VERSION 5.7 ;
  NOWIREEXTENSIONATPIN ON ;
  DIVIDERCHAR "/" ;
  BUSBITCHARS "[]" ;
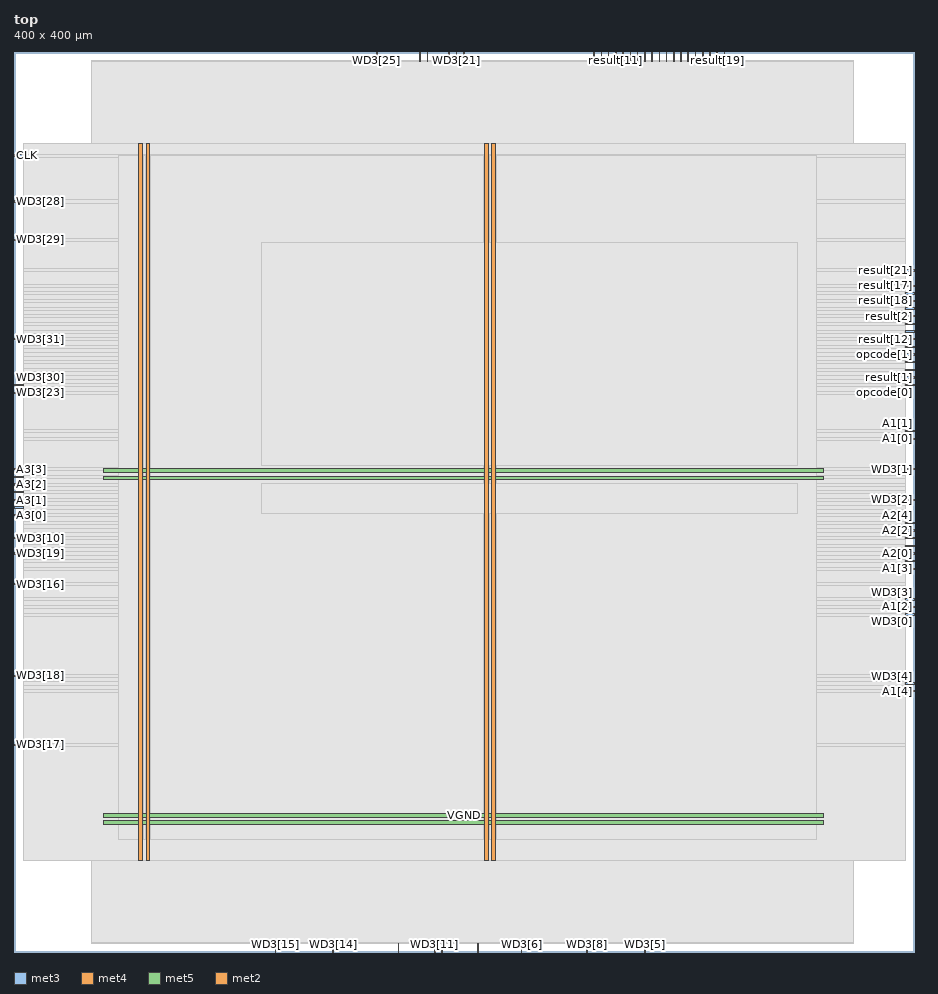
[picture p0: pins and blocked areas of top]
MACRO top
  CLASS BLOCK ;
  FOREIGN top ;
  ORIGIN 0.000 0.000 ;
  SIZE 400.000 BY 400.000 ;
  PIN A1[0]
    DIRECTION INPUT ;
    USE SIGNAL ;
    ANTENNAGATEAREA 0.126000 ;
    PORT
      LAYER met3 ;
        RECT 396.000 227.840 400.000 228.440 ;
    END
  END A1[0]
  PIN A1[1]
    DIRECTION INPUT ;
    USE SIGNAL ;
    ANTENNAGATEAREA 0.196500 ;
    PORT
      LAYER met3 ;
        RECT 396.000 231.240 400.000 231.840 ;
    END
  END A1[1]
  PIN A1[2]
    DIRECTION INPUT ;
    USE SIGNAL ;
    ANTENNAGATEAREA 0.247500 ;
    PORT
      LAYER met3 ;
        RECT 396.000 153.040 400.000 153.640 ;
    END
  END A1[2]
  PIN A1[3]
    DIRECTION INPUT ;
    USE SIGNAL ;
    ANTENNAGATEAREA 0.196500 ;
    PORT
      LAYER met3 ;
        RECT 396.000 170.040 400.000 170.640 ;
    END
  END A1[3]
  PIN A1[4]
    DIRECTION INPUT ;
    USE SIGNAL ;
    ANTENNAGATEAREA 0.213000 ;
    PORT
      LAYER met3 ;
        RECT 396.000 115.640 400.000 116.240 ;
    END
  END A1[4]
  PIN A2[0]
    DIRECTION INPUT ;
    USE SIGNAL ;
    ANTENNAGATEAREA 2.832000 ;
    PORT
      LAYER met3 ;
        RECT 396.000 173.440 400.000 174.040 ;
    END
  END A2[0]
  PIN A2[1]
    DIRECTION INPUT ;
    USE SIGNAL ;
    ANTENNAGATEAREA 0.886500 ;
    PORT
      LAYER met3 ;
        RECT 396.000 176.840 400.000 177.440 ;
    END
  END A2[1]
  PIN A2[2]
    DIRECTION INPUT ;
    USE SIGNAL ;
    ANTENNAGATEAREA 0.213000 ;
    ANTENNADIFFAREA 0.434700 ;
    PORT
      LAYER met3 ;
        RECT 396.000 187.040 400.000 187.640 ;
    END
  END A2[2]
  PIN A2[3]
    DIRECTION INPUT ;
    USE SIGNAL ;
    ANTENNAGATEAREA 0.213000 ;
    ANTENNADIFFAREA 0.434700 ;
    PORT
      LAYER met3 ;
        RECT 396.000 180.240 400.000 180.840 ;
    END
  END A2[3]
  PIN A2[4]
    DIRECTION INPUT ;
    USE SIGNAL ;
    ANTENNAGATEAREA 0.213000 ;
    PORT
      LAYER met3 ;
        RECT 396.000 190.440 400.000 191.040 ;
    END
  END A2[4]
  PIN A3[0]
    DIRECTION INPUT ;
    USE SIGNAL ;
    ANTENNAGATEAREA 0.159000 ;
    ANTENNADIFFAREA 0.434700 ;
    PORT
      LAYER met3 ;
        RECT 0.000 193.840 4.000 194.440 ;
    END
  END A3[0]
  PIN A3[1]
    DIRECTION INPUT ;
    USE SIGNAL ;
    ANTENNAGATEAREA 0.159000 ;
    ANTENNADIFFAREA 0.434700 ;
    PORT
      LAYER met3 ;
        RECT 0.000 197.240 4.000 197.840 ;
    END
  END A3[1]
  PIN A3[2]
    DIRECTION INPUT ;
    USE SIGNAL ;
    ANTENNAGATEAREA 0.196500 ;
    ANTENNADIFFAREA 0.434700 ;
    PORT
      LAYER met3 ;
        RECT 0.000 204.040 4.000 204.640 ;
    END
  END A3[2]
  PIN A3[3]
    DIRECTION INPUT ;
    USE SIGNAL ;
    ANTENNAGATEAREA 0.196500 ;
    PORT
      LAYER met3 ;
        RECT 0.000 210.840 4.000 211.440 ;
    END
  END A3[3]
  PIN A3[4]
    DIRECTION INPUT ;
    USE SIGNAL ;
    ANTENNAGATEAREA 0.196500 ;
    PORT
      LAYER met3 ;
        RECT 0.000 207.440 4.000 208.040 ;
    END
  END A3[4]
  PIN CLK
    DIRECTION INPUT ;
    USE SIGNAL ;
    ANTENNAGATEAREA 0.852000 ;
    PORT
      LAYER met3 ;
        RECT 0.000 353.640 4.000 354.240 ;
    END
  END CLK
  PIN VGND
    DIRECTION INOUT ;
    USE GROUND ;
    PORT
      LAYER met4 ;
        RECT 58.840 40.560 60.440 359.280 ;
    END
    PORT
      LAYER met4 ;
        RECT 212.440 40.560 214.040 359.280 ;
    END
    PORT
      LAYER met5 ;
        RECT 39.780 59.950 359.960 61.550 ;
    END
    PORT
      LAYER met5 ;
        RECT 39.780 213.130 359.960 214.730 ;
    END
  END VGND
  PIN VPWR
    DIRECTION INOUT ;
    USE POWER ;
    PORT
      LAYER met4 ;
        RECT 55.540 40.560 57.140 359.280 ;
    END
    PORT
      LAYER met4 ;
        RECT 209.140 40.560 210.740 359.280 ;
    END
    PORT
      LAYER met5 ;
        RECT 39.780 56.650 359.960 58.250 ;
    END
    PORT
      LAYER met5 ;
        RECT 39.780 209.830 359.960 211.430 ;
    END
  END VPWR
  PIN WD3[0]
    DIRECTION INPUT ;
    USE SIGNAL ;
    ANTENNAGATEAREA 0.196500 ;
    PORT
      LAYER met3 ;
        RECT 396.000 149.640 400.000 150.240 ;
    END
  END WD3[0]
  PIN WD3[10]
    DIRECTION INPUT ;
    USE SIGNAL ;
    ANTENNAGATEAREA 0.126000 ;
    ANTENNADIFFAREA 0.434700 ;
    PORT
      LAYER met3 ;
        RECT 0.000 183.640 4.000 184.240 ;
    END
  END WD3[10]
  PIN WD3[11]
    DIRECTION INPUT ;
    USE SIGNAL ;
    ANTENNAGATEAREA 0.213000 ;
    PORT
      LAYER met2 ;
        RECT 186.850 0.000 187.130 4.000 ;
    END
  END WD3[11]
  PIN WD3[12]
    DIRECTION INPUT ;
    USE SIGNAL ;
    ANTENNAGATEAREA 0.196500 ;
    PORT
      LAYER met2 ;
        RECT 170.750 0.000 171.030 4.000 ;
    END
  END WD3[12]
  PIN WD3[13]
    DIRECTION INPUT ;
    USE SIGNAL ;
    ANTENNAGATEAREA 0.126000 ;
    PORT
      LAYER met2 ;
        RECT 190.070 0.000 190.350 4.000 ;
    END
  END WD3[13]
  PIN WD3[14]
    DIRECTION INPUT ;
    USE SIGNAL ;
    ANTENNAGATEAREA 0.196500 ;
    PORT
      LAYER met2 ;
        RECT 141.770 0.000 142.050 4.000 ;
    END
  END WD3[14]
  PIN WD3[15]
    DIRECTION INPUT ;
    USE SIGNAL ;
    ANTENNAGATEAREA 0.196500 ;
    PORT
      LAYER met2 ;
        RECT 116.010 0.000 116.290 4.000 ;
    END
  END WD3[15]
  PIN WD3[16]
    DIRECTION INPUT ;
    USE SIGNAL ;
    ANTENNAGATEAREA 0.196500 ;
    PORT
      LAYER met3 ;
        RECT 0.000 163.240 4.000 163.840 ;
    END
  END WD3[16]
  PIN WD3[17]
    DIRECTION INPUT ;
    USE SIGNAL ;
    ANTENNAGATEAREA 0.196500 ;
    PORT
      LAYER met3 ;
        RECT 0.000 91.840 4.000 92.440 ;
    END
  END WD3[17]
  PIN WD3[18]
    DIRECTION INPUT ;
    USE SIGNAL ;
    ANTENNAGATEAREA 0.196500 ;
    PORT
      LAYER met3 ;
        RECT 0.000 122.440 4.000 123.040 ;
    END
  END WD3[18]
  PIN WD3[19]
    DIRECTION INPUT ;
    USE SIGNAL ;
    ANTENNAGATEAREA 0.196500 ;
    PORT
      LAYER met3 ;
        RECT 0.000 176.840 4.000 177.440 ;
    END
  END WD3[19]
  PIN WD3[1]
    DIRECTION INPUT ;
    USE SIGNAL ;
    ANTENNAGATEAREA 0.196500 ;
    PORT
      LAYER met3 ;
        RECT 396.000 214.240 400.000 214.840 ;
    END
  END WD3[1]
  PIN WD3[20]
    DIRECTION INPUT ;
    USE SIGNAL ;
    ANTENNAGATEAREA 0.126000 ;
    ANTENNADIFFAREA 0.434700 ;
    PORT
      LAYER met3 ;
        RECT 0.000 214.240 4.000 214.840 ;
    END
  END WD3[20]
  PIN WD3[21]
    DIRECTION INPUT ;
    USE SIGNAL ;
    ANTENNAGATEAREA 0.126000 ;
    PORT
      LAYER met2 ;
        RECT 196.510 396.000 196.790 400.000 ;
    END
  END WD3[21]
  PIN WD3[22]
    DIRECTION INPUT ;
    USE SIGNAL ;
    ANTENNAGATEAREA 0.213000 ;
    PORT
      LAYER met2 ;
        RECT 193.290 396.000 193.570 400.000 ;
    END
  END WD3[22]
  PIN WD3[23]
    DIRECTION INPUT ;
    USE SIGNAL ;
    ANTENNAGATEAREA 0.126000 ;
    ANTENNADIFFAREA 0.434700 ;
    PORT
      LAYER met3 ;
        RECT 0.000 248.240 4.000 248.840 ;
    END
  END WD3[23]
  PIN WD3[24]
    DIRECTION INPUT ;
    USE SIGNAL ;
    ANTENNAGATEAREA 0.196500 ;
    PORT
      LAYER met2 ;
        RECT 199.730 396.000 200.010 400.000 ;
    END
  END WD3[24]
  PIN WD3[25]
    DIRECTION INPUT ;
    USE SIGNAL ;
    ANTENNAGATEAREA 0.196500 ;
    PORT
      LAYER met2 ;
        RECT 161.090 396.000 161.370 400.000 ;
    END
  END WD3[25]
  PIN WD3[26]
    DIRECTION INPUT ;
    USE SIGNAL ;
    ANTENNAGATEAREA 0.196500 ;
    PORT
      LAYER met2 ;
        RECT 180.410 396.000 180.690 400.000 ;
    END
  END WD3[26]
  PIN WD3[27]
    DIRECTION INPUT ;
    USE SIGNAL ;
    ANTENNAGATEAREA 0.196500 ;
    PORT
      LAYER met2 ;
        RECT 183.630 396.000 183.910 400.000 ;
    END
  END WD3[27]
  PIN WD3[28]
    DIRECTION INPUT ;
    USE SIGNAL ;
    ANTENNAGATEAREA 0.196500 ;
    PORT
      LAYER met3 ;
        RECT 0.000 333.240 4.000 333.840 ;
    END
  END WD3[28]
  PIN WD3[29]
    DIRECTION INPUT ;
    USE SIGNAL ;
    ANTENNAGATEAREA 0.196500 ;
    PORT
      LAYER met3 ;
        RECT 0.000 316.240 4.000 316.840 ;
    END
  END WD3[29]
  PIN WD3[2]
    DIRECTION INPUT ;
    USE SIGNAL ;
    ANTENNAGATEAREA 0.196500 ;
    PORT
      LAYER met3 ;
        RECT 396.000 200.640 400.000 201.240 ;
    END
  END WD3[2]
  PIN WD3[30]
    DIRECTION INPUT ;
    USE SIGNAL ;
    ANTENNAGATEAREA 0.196500 ;
    PORT
      LAYER met3 ;
        RECT 0.000 251.640 4.000 252.240 ;
    END
  END WD3[30]
  PIN WD3[31]
    DIRECTION INPUT ;
    USE SIGNAL ;
    ANTENNAGATEAREA 0.196500 ;
    PORT
      LAYER met3 ;
        RECT 0.000 272.040 4.000 272.640 ;
    END
  END WD3[31]
  PIN WD3[3]
    DIRECTION INPUT ;
    USE SIGNAL ;
    ANTENNAGATEAREA 0.196500 ;
    PORT
      LAYER met3 ;
        RECT 396.000 156.440 400.000 157.040 ;
    END
  END WD3[3]
  PIN WD3[4]
    DIRECTION INPUT ;
    USE SIGNAL ;
    ANTENNAGATEAREA 0.196500 ;
    PORT
      LAYER met3 ;
        RECT 396.000 119.040 400.000 119.640 ;
    END
  END WD3[4]
  PIN WD3[5]
    DIRECTION INPUT ;
    USE SIGNAL ;
    ANTENNAGATEAREA 0.196500 ;
    PORT
      LAYER met2 ;
        RECT 280.230 0.000 280.510 4.000 ;
    END
  END WD3[5]
  PIN WD3[6]
    DIRECTION INPUT ;
    USE SIGNAL ;
    ANTENNAGATEAREA 0.196500 ;
    PORT
      LAYER met2 ;
        RECT 225.490 0.000 225.770 4.000 ;
    END
  END WD3[6]
  PIN WD3[7]
    DIRECTION INPUT ;
    USE SIGNAL ;
    ANTENNAGATEAREA 0.196500 ;
    PORT
      LAYER met2 ;
        RECT 206.170 0.000 206.450 4.000 ;
    END
  END WD3[7]
  PIN WD3[8]
    DIRECTION INPUT ;
    USE SIGNAL ;
    ANTENNAGATEAREA 0.196500 ;
    PORT
      LAYER met2 ;
        RECT 254.470 0.000 254.750 4.000 ;
    END
  END WD3[8]
  PIN WD3[9]
    DIRECTION INPUT ;
    USE SIGNAL ;
    ANTENNAGATEAREA 0.213000 ;
    PORT
      LAYER met3 ;
        RECT 396.000 183.640 400.000 184.240 ;
    END
  END WD3[9]
  PIN WE3
    DIRECTION INPUT ;
    USE SIGNAL ;
    ANTENNAGATEAREA 0.196500 ;
    PORT
      LAYER met3 ;
        RECT 0.000 200.640 4.000 201.240 ;
    END
  END WE3
  PIN opcode[0]
    DIRECTION INPUT ;
    USE SIGNAL ;
    ANTENNAGATEAREA 0.213000 ;
    PORT
      LAYER met3 ;
        RECT 396.000 251.640 400.000 252.240 ;
    END
  END opcode[0]
  PIN opcode[1]
    DIRECTION INPUT ;
    USE SIGNAL ;
    ANTENNAGATEAREA 0.196500 ;
    PORT
      LAYER met3 ;
        RECT 396.000 265.240 400.000 265.840 ;
    END
  END opcode[1]
  PIN result[0]
    DIRECTION OUTPUT ;
    USE SIGNAL ;
    ANTENNADIFFAREA 0.795200 ;
    PORT
      LAYER met3 ;
        RECT 396.000 278.840 400.000 279.440 ;
    END
  END result[0]
  PIN result[10]
    DIRECTION OUTPUT ;
    USE SIGNAL ;
    ANTENNADIFFAREA 0.795200 ;
    PORT
      LAYER met2 ;
        RECT 257.690 396.000 257.970 400.000 ;
    END
  END result[10]
  PIN result[11]
    DIRECTION OUTPUT ;
    USE SIGNAL ;
    ANTENNADIFFAREA 0.795200 ;
    PORT
      LAYER met2 ;
        RECT 267.350 396.000 267.630 400.000 ;
    END
  END result[11]
  PIN result[12]
    DIRECTION OUTPUT ;
    USE SIGNAL ;
    ANTENNADIFFAREA 0.795200 ;
    PORT
      LAYER met3 ;
        RECT 396.000 272.040 400.000 272.640 ;
    END
  END result[12]
  PIN result[13]
    DIRECTION OUTPUT ;
    USE SIGNAL ;
    ANTENNADIFFAREA 0.795200 ;
    PORT
      LAYER met3 ;
        RECT 396.000 268.640 400.000 269.240 ;
    END
  END result[13]
  PIN result[14]
    DIRECTION OUTPUT ;
    USE SIGNAL ;
    ANTENNADIFFAREA 0.795200 ;
    PORT
      LAYER met2 ;
        RECT 270.570 396.000 270.850 400.000 ;
    END
  END result[14]
  PIN result[15]
    DIRECTION OUTPUT ;
    USE SIGNAL ;
    ANTENNADIFFAREA 0.795200 ;
    PORT
      LAYER met3 ;
        RECT 396.000 275.440 400.000 276.040 ;
    END
  END result[15]
  PIN result[16]
    DIRECTION OUTPUT ;
    USE SIGNAL ;
    ANTENNADIFFAREA 0.795200 ;
    PORT
      LAYER met2 ;
        RECT 315.650 396.000 315.930 400.000 ;
    END
  END result[16]
  PIN result[17]
    DIRECTION OUTPUT ;
    USE SIGNAL ;
    ANTENNADIFFAREA 0.795200 ;
    PORT
      LAYER met3 ;
        RECT 396.000 295.840 400.000 296.440 ;
    END
  END result[17]
  PIN result[18]
    DIRECTION OUTPUT ;
    USE SIGNAL ;
    ANTENNADIFFAREA 0.795200 ;
    PORT
      LAYER met3 ;
        RECT 396.000 289.040 400.000 289.640 ;
    END
  END result[18]
  PIN result[19]
    DIRECTION OUTPUT ;
    USE SIGNAL ;
    ANTENNADIFFAREA 0.795200 ;
    PORT
      LAYER met2 ;
        RECT 312.430 396.000 312.710 400.000 ;
    END
  END result[19]
  PIN result[1]
    DIRECTION OUTPUT ;
    USE SIGNAL ;
    ANTENNADIFFAREA 0.795200 ;
    PORT
      LAYER met3 ;
        RECT 396.000 255.040 400.000 255.640 ;
    END
  END result[1]
  PIN result[20]
    DIRECTION OUTPUT ;
    USE SIGNAL ;
    ANTENNADIFFAREA 0.795200 ;
    PORT
      LAYER met2 ;
        RECT 289.890 396.000 290.170 400.000 ;
    END
  END result[20]
  PIN result[21]
    DIRECTION OUTPUT ;
    USE SIGNAL ;
    ANTENNADIFFAREA 0.795200 ;
    PORT
      LAYER met3 ;
        RECT 396.000 302.640 400.000 303.240 ;
    END
  END result[21]
  PIN result[22]
    DIRECTION OUTPUT ;
    USE SIGNAL ;
    ANTENNADIFFAREA 0.795200 ;
    PORT
      LAYER met2 ;
        RECT 280.230 396.000 280.510 400.000 ;
    END
  END result[22]
  PIN result[23]
    DIRECTION OUTPUT ;
    USE SIGNAL ;
    ANTENNADIFFAREA 0.795200 ;
    PORT
      LAYER met2 ;
        RECT 273.790 396.000 274.070 400.000 ;
    END
  END result[23]
  PIN result[24]
    DIRECTION OUTPUT ;
    USE SIGNAL ;
    ANTENNADIFFAREA 0.795200 ;
    PORT
      LAYER met2 ;
        RECT 309.210 396.000 309.490 400.000 ;
    END
  END result[24]
  PIN result[25]
    DIRECTION OUTPUT ;
    USE SIGNAL ;
    ANTENNADIFFAREA 0.795200 ;
    PORT
      LAYER met2 ;
        RECT 299.550 396.000 299.830 400.000 ;
    END
  END result[25]
  PIN result[26]
    DIRECTION OUTPUT ;
    USE SIGNAL ;
    ANTENNADIFFAREA 0.795200 ;
    PORT
      LAYER met2 ;
        RECT 305.990 396.000 306.270 400.000 ;
    END
  END result[26]
  PIN result[27]
    DIRECTION OUTPUT ;
    USE SIGNAL ;
    ANTENNADIFFAREA 0.795200 ;
    PORT
      LAYER met2 ;
        RECT 296.330 396.000 296.610 400.000 ;
    END
  END result[27]
  PIN result[28]
    DIRECTION OUTPUT ;
    USE SIGNAL ;
    ANTENNADIFFAREA 0.795200 ;
    PORT
      LAYER met2 ;
        RECT 286.670 396.000 286.950 400.000 ;
    END
  END result[28]
  PIN result[29]
    DIRECTION OUTPUT ;
    USE SIGNAL ;
    ANTENNADIFFAREA 0.795200 ;
    PORT
      LAYER met2 ;
        RECT 283.450 396.000 283.730 400.000 ;
    END
  END result[29]
  PIN result[2]
    DIRECTION OUTPUT ;
    USE SIGNAL ;
    ANTENNADIFFAREA 0.795200 ;
    PORT
      LAYER met3 ;
        RECT 396.000 282.240 400.000 282.840 ;
    END
  END result[2]
  PIN result[30]
    DIRECTION OUTPUT ;
    USE SIGNAL ;
    ANTENNADIFFAREA 0.795200 ;
    PORT
      LAYER met2 ;
        RECT 293.110 396.000 293.390 400.000 ;
    END
  END result[30]
  PIN result[31]
    DIRECTION OUTPUT ;
    USE SIGNAL ;
    ANTENNADIFFAREA 0.891000 ;
    PORT
      LAYER met2 ;
        RECT 260.910 396.000 261.190 400.000 ;
    END
  END result[31]
  PIN result[3]
    DIRECTION OUTPUT ;
    USE SIGNAL ;
    ANTENNADIFFAREA 0.795200 ;
    PORT
      LAYER met3 ;
        RECT 396.000 261.840 400.000 262.440 ;
    END
  END result[3]
  PIN result[4]
    DIRECTION OUTPUT ;
    USE SIGNAL ;
    ANTENNADIFFAREA 0.795200 ;
    PORT
      LAYER met3 ;
        RECT 396.000 285.640 400.000 286.240 ;
    END
  END result[4]
  PIN result[5]
    DIRECTION OUTPUT ;
    USE SIGNAL ;
    ANTENNADIFFAREA 0.795200 ;
    PORT
      LAYER met3 ;
        RECT 396.000 292.440 400.000 293.040 ;
    END
  END result[5]
  PIN result[6]
    DIRECTION OUTPUT ;
    USE SIGNAL ;
    ANTENNADIFFAREA 0.795200 ;
    PORT
      LAYER met2 ;
        RECT 302.770 396.000 303.050 400.000 ;
    END
  END result[6]
  PIN result[7]
    DIRECTION OUTPUT ;
    USE SIGNAL ;
    ANTENNADIFFAREA 0.795200 ;
    PORT
      LAYER met3 ;
        RECT 396.000 258.440 400.000 259.040 ;
    END
  END result[7]
  PIN result[8]
    DIRECTION OUTPUT ;
    USE SIGNAL ;
    ANTENNADIFFAREA 0.795200 ;
    PORT
      LAYER met2 ;
        RECT 277.010 396.000 277.290 400.000 ;
    END
  END result[8]
  PIN result[9]
    DIRECTION OUTPUT ;
    USE SIGNAL ;
    ANTENNADIFFAREA 0.795200 ;
    PORT
      LAYER met2 ;
        RECT 264.130 396.000 264.410 400.000 ;
    END
  END result[9]
  OBS
      LAYER nwell ;
        RECT 39.830 40.715 359.910 359.230 ;
      LAYER li1 ;
        RECT 40.020 40.715 359.720 359.125 ;
      LAYER met1 ;
        RECT 34.570 40.560 372.990 384.500 ;
      LAYER met2 ;
        RECT 34.590 395.720 160.810 396.170 ;
        RECT 161.650 395.720 180.130 396.170 ;
        RECT 180.970 395.720 183.350 396.170 ;
        RECT 184.190 395.720 193.010 396.170 ;
        RECT 193.850 395.720 196.230 396.170 ;
        RECT 197.070 395.720 199.450 396.170 ;
        RECT 200.290 395.720 257.410 396.170 ;
        RECT 258.250 395.720 260.630 396.170 ;
        RECT 261.470 395.720 263.850 396.170 ;
        RECT 264.690 395.720 267.070 396.170 ;
        RECT 267.910 395.720 270.290 396.170 ;
        RECT 271.130 395.720 273.510 396.170 ;
        RECT 274.350 395.720 276.730 396.170 ;
        RECT 277.570 395.720 279.950 396.170 ;
        RECT 280.790 395.720 283.170 396.170 ;
        RECT 284.010 395.720 286.390 396.170 ;
        RECT 287.230 395.720 289.610 396.170 ;
        RECT 290.450 395.720 292.830 396.170 ;
        RECT 293.670 395.720 296.050 396.170 ;
        RECT 296.890 395.720 299.270 396.170 ;
        RECT 300.110 395.720 302.490 396.170 ;
        RECT 303.330 395.720 305.710 396.170 ;
        RECT 306.550 395.720 308.930 396.170 ;
        RECT 309.770 395.720 312.150 396.170 ;
        RECT 312.990 395.720 315.370 396.170 ;
        RECT 316.210 395.720 372.970 396.170 ;
        RECT 34.590 4.280 372.970 395.720 ;
        RECT 34.590 3.670 115.730 4.280 ;
        RECT 116.570 3.670 141.490 4.280 ;
        RECT 142.330 3.670 170.470 4.280 ;
        RECT 171.310 3.670 186.570 4.280 ;
        RECT 187.410 3.670 189.790 4.280 ;
        RECT 190.630 3.670 205.890 4.280 ;
        RECT 206.730 3.670 225.210 4.280 ;
        RECT 226.050 3.670 254.190 4.280 ;
        RECT 255.030 3.670 279.950 4.280 ;
        RECT 280.790 3.670 372.970 4.280 ;
      LAYER met3 ;
        RECT 4.000 354.640 396.000 359.205 ;
        RECT 4.400 353.240 396.000 354.640 ;
        RECT 4.000 334.240 396.000 353.240 ;
        RECT 4.400 332.840 396.000 334.240 ;
        RECT 4.000 317.240 396.000 332.840 ;
        RECT 4.400 315.840 396.000 317.240 ;
        RECT 4.000 303.640 396.000 315.840 ;
        RECT 4.000 302.240 395.600 303.640 ;
        RECT 4.000 296.840 396.000 302.240 ;
        RECT 4.000 295.440 395.600 296.840 ;
        RECT 4.000 293.440 396.000 295.440 ;
        RECT 4.000 292.040 395.600 293.440 ;
        RECT 4.000 290.040 396.000 292.040 ;
        RECT 4.000 288.640 395.600 290.040 ;
        RECT 4.000 286.640 396.000 288.640 ;
        RECT 4.000 285.240 395.600 286.640 ;
        RECT 4.000 283.240 396.000 285.240 ;
        RECT 4.000 281.840 395.600 283.240 ;
        RECT 4.000 279.840 396.000 281.840 ;
        RECT 4.000 278.440 395.600 279.840 ;
        RECT 4.000 276.440 396.000 278.440 ;
        RECT 4.000 275.040 395.600 276.440 ;
        RECT 4.000 273.040 396.000 275.040 ;
        RECT 4.400 271.640 395.600 273.040 ;
        RECT 4.000 269.640 396.000 271.640 ;
        RECT 4.000 268.240 395.600 269.640 ;
        RECT 4.000 266.240 396.000 268.240 ;
        RECT 4.000 264.840 395.600 266.240 ;
        RECT 4.000 262.840 396.000 264.840 ;
        RECT 4.000 261.440 395.600 262.840 ;
        RECT 4.000 259.440 396.000 261.440 ;
        RECT 4.000 258.040 395.600 259.440 ;
        RECT 4.000 256.040 396.000 258.040 ;
        RECT 4.000 254.640 395.600 256.040 ;
        RECT 4.000 252.640 396.000 254.640 ;
        RECT 4.400 251.240 395.600 252.640 ;
        RECT 4.000 249.240 396.000 251.240 ;
        RECT 4.400 247.840 396.000 249.240 ;
        RECT 4.000 232.240 396.000 247.840 ;
        RECT 4.000 230.840 395.600 232.240 ;
        RECT 4.000 228.840 396.000 230.840 ;
        RECT 4.000 227.440 395.600 228.840 ;
        RECT 4.000 215.240 396.000 227.440 ;
        RECT 4.400 213.840 395.600 215.240 ;
        RECT 4.000 211.840 396.000 213.840 ;
        RECT 4.400 210.440 396.000 211.840 ;
        RECT 4.000 208.440 396.000 210.440 ;
        RECT 4.400 207.040 396.000 208.440 ;
        RECT 4.000 205.040 396.000 207.040 ;
        RECT 4.400 203.640 396.000 205.040 ;
        RECT 4.000 201.640 396.000 203.640 ;
        RECT 4.400 200.240 395.600 201.640 ;
        RECT 4.000 198.240 396.000 200.240 ;
        RECT 4.400 196.840 396.000 198.240 ;
        RECT 4.000 194.840 396.000 196.840 ;
        RECT 4.400 193.440 396.000 194.840 ;
        RECT 4.000 191.440 396.000 193.440 ;
        RECT 4.000 190.040 395.600 191.440 ;
        RECT 4.000 188.040 396.000 190.040 ;
        RECT 4.000 186.640 395.600 188.040 ;
        RECT 4.000 184.640 396.000 186.640 ;
        RECT 4.400 183.240 395.600 184.640 ;
        RECT 4.000 181.240 396.000 183.240 ;
        RECT 4.000 179.840 395.600 181.240 ;
        RECT 4.000 177.840 396.000 179.840 ;
        RECT 4.400 176.440 395.600 177.840 ;
        RECT 4.000 174.440 396.000 176.440 ;
        RECT 4.000 173.040 395.600 174.440 ;
        RECT 4.000 171.040 396.000 173.040 ;
        RECT 4.000 169.640 395.600 171.040 ;
        RECT 4.000 164.240 396.000 169.640 ;
        RECT 4.400 162.840 396.000 164.240 ;
        RECT 4.000 157.440 396.000 162.840 ;
        RECT 4.000 156.040 395.600 157.440 ;
        RECT 4.000 154.040 396.000 156.040 ;
        RECT 4.000 152.640 395.600 154.040 ;
        RECT 4.000 150.640 396.000 152.640 ;
        RECT 4.000 149.240 395.600 150.640 ;
        RECT 4.000 123.440 396.000 149.240 ;
        RECT 4.400 122.040 396.000 123.440 ;
        RECT 4.000 120.040 396.000 122.040 ;
        RECT 4.000 118.640 395.600 120.040 ;
        RECT 4.000 116.640 396.000 118.640 ;
        RECT 4.000 115.240 395.600 116.640 ;
        RECT 4.000 92.840 396.000 115.240 ;
        RECT 4.400 91.440 396.000 92.840 ;
        RECT 4.000 40.635 396.000 91.440 ;
      LAYER met4 ;
        RECT 46.295 49.815 55.140 354.105 ;
        RECT 57.540 49.815 58.440 354.105 ;
        RECT 60.840 49.815 208.740 354.105 ;
        RECT 211.140 49.815 212.040 354.105 ;
        RECT 214.440 49.815 356.665 354.105 ;
      LAYER met5 ;
        RECT 110.060 216.330 348.100 315.300 ;
        RECT 110.060 194.700 348.100 208.230 ;
  END
END top
END LIBRARY

